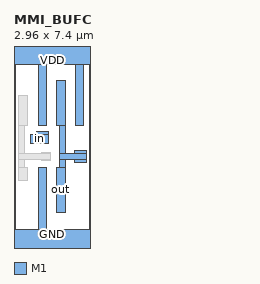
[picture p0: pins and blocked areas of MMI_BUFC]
MACRO MMI_BUFC
	CLASS CORE ;
	FOREIGN MMI_BUFC 0 0 ;
	SIZE 2.96 BY 7.4 ;
	SYMMETRY X Y ;
	SITE CORE1 ;
	PIN out
		DIRECTION output ;
		USE SIGNAL ;
		PORT
			LAYER M1 ;
			RECT 1.66 4.53 2 6.29 ;
			LAYER M1 ;
			RECT 1.77 3.445 2 4.53 ;
			LAYER M1 ;
			RECT 2.365 3.445 2.815 3.555 ;
			LAYER M1 ;
			RECT 1.77 3.215 2.815 3.445 ;
			LAYER M1 ;
			RECT 1.77 2.92 2 3.215 ;
			LAYER M1 ;
			RECT 2.365 3.105 2.815 3.215 ;
			LAYER M1 ;
			RECT 1.66 1.16 2 2.92 ;
		END
		AntennaDiffArea 1.8768 ;
	END out
	PIN GND
		DIRECTION inout ;
		USE GROUND ;
		PORT
			LAYER M1 ;
			RECT 0.94 0.5 1.28 2.92 ;
			LAYER M1 ;
			RECT 0 -0.5 2.96 0.5 ;
		END
	END GND
	PIN VDD
		DIRECTION inout ;
		USE POWER ;
		PORT
			LAYER M1 ;
			RECT 0 6.9 2.96 7.9 ;
			LAYER M1 ;
			RECT 0.94 4.53 1.28 6.9 ;
			LAYER M1 ;
			RECT 2.38 4.53 2.72 6.9 ;
		END
	END VDD
	PIN in
		DIRECTION input ;
		USE SIGNAL ;
		PORT
			LAYER M1 ;
			RECT 0.885 4.19 1.335 4.295 ;
			LAYER M1 ;
			RECT 0.64 3.85 1.335 4.19 ;
			LAYER M1 ;
			RECT 0.885 3.845 1.335 3.85 ;
		END
		AntennaGateArea 0.3348 ;
	END in
	OBS
		LAYER M1 ;
		RECT 0.18 4.53 0.52 5.69 ;
		LAYER M1 ;
		RECT 0.18 3.445 0.41 4.53 ;
		LAYER M1 ;
		RECT 1.09 3.445 1.43 3.5 ;
		LAYER M1 ;
		RECT 0.18 3.215 1.43 3.445 ;
		LAYER M1 ;
		RECT 0.18 2.92 0.41 3.215 ;
		LAYER M1 ;
		RECT 1.09 3.16 1.43 3.215 ;
		LAYER M1 ;
		RECT 0.18 2.38 0.52 2.92 ;
	END
END MMI_BUFC
